VERSION 5.8 ;
BUSBITCHARS "[]" ;
DIVIDERCHAR "/" ;
UNITS
    DATABASE MICRONS 2000 ;
END UNITS

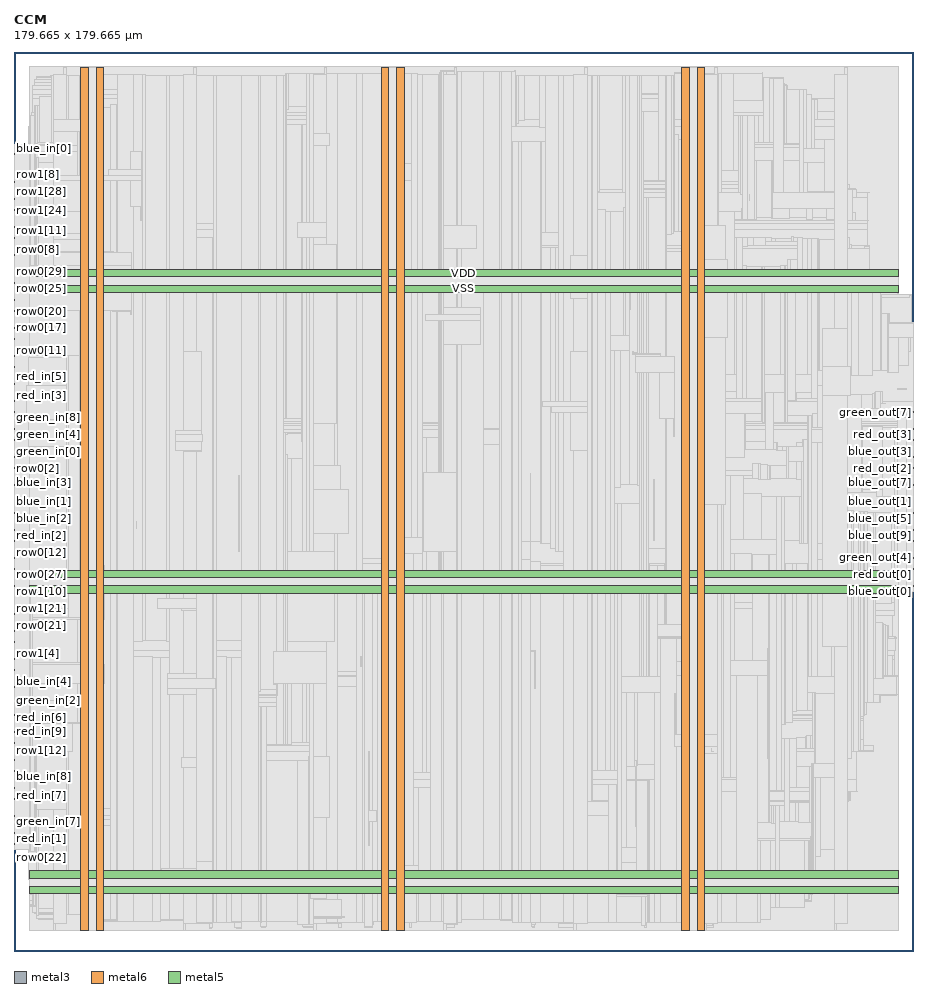
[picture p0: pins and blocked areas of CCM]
MACRO CCM
  FOREIGN CCM 0 0 ;
  CLASS BLOCK ;
  SIZE 179.665 BY 179.665 ;
  PIN blue_in[0]
    DIRECTION INPUT ;
    USE SIGNAL ;
    PORT
      LAYER metal3 ;
        RECT  0 160.195 0.07 160.265 ;
    END
  END blue_in[0]
  PIN blue_in[1]
    DIRECTION INPUT ;
    USE SIGNAL ;
    PORT
      LAYER metal3 ;
        RECT  0 89.635 0.07 89.705 ;
    END
  END blue_in[1]
  PIN blue_in[2]
    DIRECTION INPUT ;
    USE SIGNAL ;
    PORT
      LAYER metal3 ;
        RECT  0 86.275 0.07 86.345 ;
    END
  END blue_in[2]
  PIN blue_in[3]
    DIRECTION INPUT ;
    USE SIGNAL ;
    PORT
      LAYER metal3 ;
        RECT  0 91.875 0.07 91.945 ;
    END
  END blue_in[3]
  PIN blue_in[4]
    DIRECTION INPUT ;
    USE SIGNAL ;
    PORT
      LAYER metal3 ;
        RECT  0 53.795 0.07 53.865 ;
    END
  END blue_in[4]
  PIN blue_in[5]
    DIRECTION INPUT ;
    USE SIGNAL ;
    PORT
      LAYER metal3 ;
        RECT  0 88.515 0.07 88.585 ;
    END
  END blue_in[5]
  PIN blue_in[6]
    DIRECTION INPUT ;
    USE SIGNAL ;
    PORT
      LAYER metal3 ;
        RECT  0 94.115 0.07 94.185 ;
    END
  END blue_in[6]
  PIN blue_in[7]
    DIRECTION INPUT ;
    USE SIGNAL ;
    PORT
      LAYER metal3 ;
        RECT  0 95.235 0.07 95.305 ;
    END
  END blue_in[7]
  PIN blue_in[8]
    DIRECTION INPUT ;
    USE SIGNAL ;
    PORT
      LAYER metal3 ;
        RECT  0 34.755 0.07 34.825 ;
    END
  END blue_in[8]
  PIN blue_in[9]
    DIRECTION INPUT ;
    USE SIGNAL ;
    PORT
      LAYER metal3 ;
        RECT  0 52.675 0.07 52.745 ;
    END
  END blue_in[9]
  PIN blue_out[0]
    DIRECTION OUTPUT ;
    USE SIGNAL ;
    PORT
      LAYER metal3 ;
        RECT  179.595 71.715 179.665 71.785 ;
    END
  END blue_out[0]
  PIN blue_out[1]
    DIRECTION OUTPUT ;
    USE SIGNAL ;
    PORT
      LAYER metal3 ;
        RECT  179.595 89.635 179.665 89.705 ;
    END
  END blue_out[1]
  PIN blue_out[2]
    DIRECTION OUTPUT ;
    USE SIGNAL ;
    PORT
      LAYER metal3 ;
        RECT  179.595 104.195 179.665 104.265 ;
    END
  END blue_out[2]
  PIN blue_out[3]
    DIRECTION OUTPUT ;
    USE SIGNAL ;
    PORT
      LAYER metal3 ;
        RECT  179.595 99.715 179.665 99.785 ;
    END
  END blue_out[3]
  PIN blue_out[4]
    DIRECTION OUTPUT ;
    USE SIGNAL ;
    PORT
      LAYER metal3 ;
        RECT  179.595 94.115 179.665 94.185 ;
    END
  END blue_out[4]
  PIN blue_out[5]
    DIRECTION OUTPUT ;
    USE SIGNAL ;
    PORT
      LAYER metal3 ;
        RECT  179.595 86.275 179.665 86.345 ;
    END
  END blue_out[5]
  PIN blue_out[6]
    DIRECTION OUTPUT ;
    USE SIGNAL ;
    PORT
      LAYER metal3 ;
        RECT  179.595 85.155 179.665 85.225 ;
    END
  END blue_out[6]
  PIN blue_out[7]
    DIRECTION OUTPUT ;
    USE SIGNAL ;
    PORT
      LAYER metal3 ;
        RECT  179.595 91.875 179.665 91.945 ;
    END
  END blue_out[7]
  PIN blue_out[8]
    DIRECTION OUTPUT ;
    USE SIGNAL ;
    PORT
      LAYER metal3 ;
        RECT  179.595 100.835 179.665 100.905 ;
    END
  END blue_out[8]
  PIN blue_out[9]
    DIRECTION OUTPUT ;
    USE SIGNAL ;
    PORT
      LAYER metal3 ;
        RECT  179.595 82.915 179.665 82.985 ;
    END
  END blue_out[9]
  PIN clk
    DIRECTION INPUT ;
    USE SIGNAL ;
    PORT
      LAYER metal3 ;
        RECT  0 97.475 0.07 97.545 ;
    END
  END clk
  PIN coef_in
    DIRECTION INPUT ;
    USE SIGNAL ;
    PORT
      LAYER metal3 ;
        RECT  0 98.595 0.07 98.665 ;
    END
  END coef_in
  PIN green_in[0]
    DIRECTION INPUT ;
    USE SIGNAL ;
    PORT
      LAYER metal3 ;
        RECT  0 99.715 0.07 99.785 ;
    END
  END green_in[0]
  PIN green_in[1]
    DIRECTION INPUT ;
    USE SIGNAL ;
    PORT
      LAYER metal3 ;
        RECT  0 76.195 0.07 76.265 ;
    END
  END green_in[1]
  PIN green_in[2]
    DIRECTION INPUT ;
    USE SIGNAL ;
    PORT
      LAYER metal3 ;
        RECT  0 51.555 0.07 51.625 ;
    END
  END green_in[2]
  PIN green_in[3]
    DIRECTION INPUT ;
    USE SIGNAL ;
    PORT
      LAYER metal3 ;
        RECT  0 101.955 0.07 102.025 ;
    END
  END green_in[3]
  PIN green_in[4]
    DIRECTION INPUT ;
    USE SIGNAL ;
    PORT
      LAYER metal3 ;
        RECT  0 103.075 0.07 103.145 ;
    END
  END green_in[4]
  PIN green_in[5]
    DIRECTION INPUT ;
    USE SIGNAL ;
    PORT
      LAYER metal3 ;
        RECT  0 85.155 0.07 85.225 ;
    END
  END green_in[5]
  PIN green_in[6]
    DIRECTION INPUT ;
    USE SIGNAL ;
    PORT
      LAYER metal3 ;
        RECT  0 33.635 0.07 33.705 ;
    END
  END green_in[6]
  PIN green_in[7]
    DIRECTION INPUT ;
    USE SIGNAL ;
    PORT
      LAYER metal3 ;
        RECT  0 25.795 0.07 25.865 ;
    END
  END green_in[7]
  PIN green_in[8]
    DIRECTION INPUT ;
    USE SIGNAL ;
    PORT
      LAYER metal3 ;
        RECT  0 106.435 0.07 106.505 ;
    END
  END green_in[8]
  PIN green_in[9]
    DIRECTION INPUT ;
    USE SIGNAL ;
    PORT
      LAYER metal3 ;
        RECT  0 84.035 0.07 84.105 ;
    END
  END green_in[9]
  PIN green_out[0]
    DIRECTION OUTPUT ;
    USE SIGNAL ;
    PORT
      LAYER metal3 ;
        RECT  179.595 81.795 179.665 81.865 ;
    END
  END green_out[0]
  PIN green_out[1]
    DIRECTION OUTPUT ;
    USE SIGNAL ;
    PORT
      LAYER metal3 ;
        RECT  179.595 92.995 179.665 93.065 ;
    END
  END green_out[1]
  PIN green_out[2]
    DIRECTION OUTPUT ;
    USE SIGNAL ;
    PORT
      LAYER metal3 ;
        RECT  179.595 80.675 179.665 80.745 ;
    END
  END green_out[2]
  PIN green_out[3]
    DIRECTION OUTPUT ;
    USE SIGNAL ;
    PORT
      LAYER metal3 ;
        RECT  179.595 101.955 179.665 102.025 ;
    END
  END green_out[3]
  PIN green_out[4]
    DIRECTION OUTPUT ;
    USE SIGNAL ;
    PORT
      LAYER metal3 ;
        RECT  179.595 78.435 179.665 78.505 ;
    END
  END green_out[4]
  PIN green_out[5]
    DIRECTION OUTPUT ;
    USE SIGNAL ;
    PORT
      LAYER metal3 ;
        RECT  179.595 105.315 179.665 105.385 ;
    END
  END green_out[5]
  PIN green_out[6]
    DIRECTION OUTPUT ;
    USE SIGNAL ;
    PORT
      LAYER metal3 ;
        RECT  179.595 88.515 179.665 88.585 ;
    END
  END green_out[6]
  PIN green_out[7]
    DIRECTION OUTPUT ;
    USE SIGNAL ;
    PORT
      LAYER metal3 ;
        RECT  179.595 107.555 179.665 107.625 ;
    END
  END green_out[7]
  PIN green_out[8]
    DIRECTION OUTPUT ;
    USE SIGNAL ;
    PORT
      LAYER metal3 ;
        RECT  179.595 77.315 179.665 77.385 ;
    END
  END green_out[8]
  PIN green_out[9]
    DIRECTION OUTPUT ;
    USE SIGNAL ;
    PORT
      LAYER metal3 ;
        RECT  179.595 95.235 179.665 95.305 ;
    END
  END green_out[9]
  PIN h_sync
    DIRECTION INPUT ;
    USE SIGNAL ;
    PORT
      LAYER metal3 ;
        RECT  0 107.555 0.07 107.625 ;
    END
  END h_sync
  PIN h_sync_out
    DIRECTION OUTPUT ;
    USE SIGNAL ;
    PORT
      LAYER metal3 ;
        RECT  179.595 84.035 179.665 84.105 ;
    END
  END h_sync_out
  PIN red_in[0]
    DIRECTION INPUT ;
    USE SIGNAL ;
    PORT
      LAYER metal3 ;
        RECT  0 108.675 0.07 108.745 ;
    END
  END red_in[0]
  PIN red_in[1]
    DIRECTION INPUT ;
    USE SIGNAL ;
    PORT
      LAYER metal3 ;
        RECT  0 22.435 0.07 22.505 ;
    END
  END red_in[1]
  PIN red_in[2]
    DIRECTION INPUT ;
    USE SIGNAL ;
    PORT
      LAYER metal3 ;
        RECT  0 82.915 0.07 82.985 ;
    END
  END red_in[2]
  PIN red_in[3]
    DIRECTION INPUT ;
    USE SIGNAL ;
    PORT
      LAYER metal3 ;
        RECT  0 110.915 0.07 110.985 ;
    END
  END red_in[3]
  PIN red_in[4]
    DIRECTION INPUT ;
    USE SIGNAL ;
    PORT
      LAYER metal3 ;
        RECT  0 112.035 0.07 112.105 ;
    END
  END red_in[4]
  PIN red_in[5]
    DIRECTION INPUT ;
    USE SIGNAL ;
    PORT
      LAYER metal3 ;
        RECT  0 113.155 0.07 113.225 ;
    END
  END red_in[5]
  PIN red_in[6]
    DIRECTION INPUT ;
    USE SIGNAL ;
    PORT
      LAYER metal3 ;
        RECT  0 48.195 0.07 48.265 ;
    END
  END red_in[6]
  PIN red_in[7]
    DIRECTION INPUT ;
    USE SIGNAL ;
    PORT
      LAYER metal3 ;
        RECT  0 32.515 0.07 32.585 ;
    END
  END red_in[7]
  PIN red_in[8]
    DIRECTION INPUT ;
    USE SIGNAL ;
    PORT
      LAYER metal3 ;
        RECT  0 44.835 0.07 44.905 ;
    END
  END red_in[8]
  PIN red_in[9]
    DIRECTION INPUT ;
    USE SIGNAL ;
    PORT
      LAYER metal3 ;
        RECT  0 43.715 0.07 43.785 ;
    END
  END red_in[9]
  PIN red_out[0]
    DIRECTION OUTPUT ;
    USE SIGNAL ;
    PORT
      LAYER metal3 ;
        RECT  179.595 75.075 179.665 75.145 ;
    END
  END red_out[0]
  PIN red_out[1]
    DIRECTION OUTPUT ;
    USE SIGNAL ;
    PORT
      LAYER metal3 ;
        RECT  179.595 87.395 179.665 87.465 ;
    END
  END red_out[1]
  PIN red_out[2]
    DIRECTION OUTPUT ;
    USE SIGNAL ;
    PORT
      LAYER metal3 ;
        RECT  179.595 96.355 179.665 96.425 ;
    END
  END red_out[2]
  PIN red_out[3]
    DIRECTION OUTPUT ;
    USE SIGNAL ;
    PORT
      LAYER metal3 ;
        RECT  179.595 103.075 179.665 103.145 ;
    END
  END red_out[3]
  PIN red_out[4]
    DIRECTION OUTPUT ;
    USE SIGNAL ;
    PORT
      LAYER metal3 ;
        RECT  179.595 90.755 179.665 90.825 ;
    END
  END red_out[4]
  PIN red_out[5]
    DIRECTION OUTPUT ;
    USE SIGNAL ;
    PORT
      LAYER metal3 ;
        RECT  179.595 73.955 179.665 74.025 ;
    END
  END red_out[5]
  PIN red_out[6]
    DIRECTION OUTPUT ;
    USE SIGNAL ;
    PORT
      LAYER metal3 ;
        RECT  179.595 97.475 179.665 97.545 ;
    END
  END red_out[6]
  PIN red_out[7]
    DIRECTION OUTPUT ;
    USE SIGNAL ;
    PORT
      LAYER metal3 ;
        RECT  179.595 72.835 179.665 72.905 ;
    END
  END red_out[7]
  PIN red_out[8]
    DIRECTION OUTPUT ;
    USE SIGNAL ;
    PORT
      LAYER metal3 ;
        RECT  179.595 79.555 179.665 79.625 ;
    END
  END red_out[8]
  PIN red_out[9]
    DIRECTION OUTPUT ;
    USE SIGNAL ;
    PORT
      LAYER metal3 ;
        RECT  179.595 76.195 179.665 76.265 ;
    END
  END red_out[9]
  PIN resetn
    DIRECTION INPUT ;
    USE SIGNAL ;
    PORT
      LAYER metal3 ;
        RECT  0 80.675 0.07 80.745 ;
    END
  END resetn
  PIN row0[0]
    DIRECTION INPUT ;
    USE SIGNAL ;
    PORT
      LAYER metal3 ;
        RECT  0 47.075 0.07 47.145 ;
    END
  END row0[0]
  PIN row0[10]
    DIRECTION INPUT ;
    USE SIGNAL ;
    PORT
      LAYER metal3 ;
        RECT  0 118.755 0.07 118.825 ;
    END
  END row0[10]
  PIN row0[11]
    DIRECTION INPUT ;
    USE SIGNAL ;
    PORT
      LAYER metal3 ;
        RECT  0 119.875 0.07 119.945 ;
    END
  END row0[11]
  PIN row0[12]
    DIRECTION INPUT ;
    USE SIGNAL ;
    PORT
      LAYER metal3 ;
        RECT  0 79.555 0.07 79.625 ;
    END
  END row0[12]
  PIN row0[13]
    DIRECTION INPUT ;
    USE SIGNAL ;
    PORT
      LAYER metal3 ;
        RECT  0 115.395 0.07 115.465 ;
    END
  END row0[13]
  PIN row0[14]
    DIRECTION INPUT ;
    USE SIGNAL ;
    PORT
      LAYER metal3 ;
        RECT  0 45.955 0.07 46.025 ;
    END
  END row0[14]
  PIN row0[15]
    DIRECTION INPUT ;
    USE SIGNAL ;
    PORT
      LAYER metal3 ;
        RECT  0 123.235 0.07 123.305 ;
    END
  END row0[15]
  PIN row0[16]
    DIRECTION INPUT ;
    USE SIGNAL ;
    PORT
      LAYER metal3 ;
        RECT  0 78.435 0.07 78.505 ;
    END
  END row0[16]
  PIN row0[17]
    DIRECTION INPUT ;
    USE SIGNAL ;
    PORT
      LAYER metal3 ;
        RECT  0 124.355 0.07 124.425 ;
    END
  END row0[17]
  PIN row0[18]
    DIRECTION INPUT ;
    USE SIGNAL ;
    PORT
      LAYER metal3 ;
        RECT  0 125.475 0.07 125.545 ;
    END
  END row0[18]
  PIN row0[19]
    DIRECTION INPUT ;
    USE SIGNAL ;
    PORT
      LAYER metal3 ;
        RECT  0 31.395 0.07 31.465 ;
    END
  END row0[19]
  PIN row0[1]
    DIRECTION INPUT ;
    USE SIGNAL ;
    PORT
      LAYER metal3 ;
        RECT  0 77.315 0.07 77.385 ;
    END
  END row0[1]
  PIN row0[20]
    DIRECTION INPUT ;
    USE SIGNAL ;
    PORT
      LAYER metal3 ;
        RECT  0 127.715 0.07 127.785 ;
    END
  END row0[20]
  PIN row0[21]
    DIRECTION INPUT ;
    USE SIGNAL ;
    PORT
      LAYER metal3 ;
        RECT  0 64.995 0.07 65.065 ;
    END
  END row0[21]
  PIN row0[22]
    DIRECTION INPUT ;
    USE SIGNAL ;
    PORT
      LAYER metal3 ;
        RECT  0 20.195 0.07 20.265 ;
    END
  END row0[22]
  PIN row0[23]
    DIRECTION INPUT ;
    USE SIGNAL ;
    PORT
      LAYER metal3 ;
        RECT  0 24.675 0.07 24.745 ;
    END
  END row0[23]
  PIN row0[24]
    DIRECTION INPUT ;
    USE SIGNAL ;
    PORT
      LAYER metal3 ;
        RECT  0 81.795 0.07 81.865 ;
    END
  END row0[24]
  PIN row0[25]
    DIRECTION INPUT ;
    USE SIGNAL ;
    PORT
      LAYER metal3 ;
        RECT  0 132.195 0.07 132.265 ;
    END
  END row0[25]
  PIN row0[26]
    DIRECTION INPUT ;
    USE SIGNAL ;
    PORT
      LAYER metal3 ;
        RECT  0 128.835 0.07 128.905 ;
    END
  END row0[26]
  PIN row0[27]
    DIRECTION INPUT ;
    USE SIGNAL ;
    PORT
      LAYER metal3 ;
        RECT  0 75.075 0.07 75.145 ;
    END
  END row0[27]
  PIN row0[28]
    DIRECTION INPUT ;
    USE SIGNAL ;
    PORT
      LAYER metal3 ;
        RECT  0 104.195 0.07 104.265 ;
    END
  END row0[28]
  PIN row0[29]
    DIRECTION INPUT ;
    USE SIGNAL ;
    PORT
      LAYER metal3 ;
        RECT  0 135.555 0.07 135.625 ;
    END
  END row0[29]
  PIN row0[2]
    DIRECTION INPUT ;
    USE SIGNAL ;
    PORT
      LAYER metal3 ;
        RECT  0 96.355 0.07 96.425 ;
    END
  END row0[2]
  PIN row0[3]
    DIRECTION INPUT ;
    USE SIGNAL ;
    PORT
      LAYER metal3 ;
        RECT  0 73.955 0.07 74.025 ;
    END
  END row0[3]
  PIN row0[4]
    DIRECTION INPUT ;
    USE SIGNAL ;
    PORT
      LAYER metal3 ;
        RECT  0 42.595 0.07 42.665 ;
    END
  END row0[4]
  PIN row0[5]
    DIRECTION INPUT ;
    USE SIGNAL ;
    PORT
      LAYER metal3 ;
        RECT  0 30.275 0.07 30.345 ;
    END
  END row0[5]
  PIN row0[6]
    DIRECTION INPUT ;
    USE SIGNAL ;
    PORT
      LAYER metal3 ;
        RECT  0 138.915 0.07 138.985 ;
    END
  END row0[6]
  PIN row0[7]
    DIRECTION INPUT ;
    USE SIGNAL ;
    PORT
      LAYER metal3 ;
        RECT  0 72.835 0.07 72.905 ;
    END
  END row0[7]
  PIN row0[8]
    DIRECTION INPUT ;
    USE SIGNAL ;
    PORT
      LAYER metal3 ;
        RECT  0 140.035 0.07 140.105 ;
    END
  END row0[8]
  PIN row0[9]
    DIRECTION INPUT ;
    USE SIGNAL ;
    PORT
      LAYER metal3 ;
        RECT  0 141.155 0.07 141.225 ;
    END
  END row0[9]
  PIN row1[0]
    DIRECTION INPUT ;
    USE SIGNAL ;
    PORT
      LAYER metal3 ;
        RECT  0 126.595 0.07 126.665 ;
    END
  END row1[0]
  PIN row1[10]
    DIRECTION INPUT ;
    USE SIGNAL ;
    PORT
      LAYER metal3 ;
        RECT  0 71.715 0.07 71.785 ;
    END
  END row1[10]
  PIN row1[11]
    DIRECTION INPUT ;
    USE SIGNAL ;
    PORT
      LAYER metal3 ;
        RECT  0 142.275 0.07 142.345 ;
    END
  END row1[11]
  PIN row1[12]
    DIRECTION INPUT ;
    USE SIGNAL ;
    PORT
      LAYER metal3 ;
        RECT  0 41.475 0.07 41.545 ;
    END
  END row1[12]
  PIN row1[13]
    DIRECTION INPUT ;
    USE SIGNAL ;
    PORT
      LAYER metal3 ;
        RECT  0 116.515 0.07 116.585 ;
    END
  END row1[13]
  PIN row1[14]
    DIRECTION INPUT ;
    USE SIGNAL ;
    PORT
      LAYER metal3 ;
        RECT  0 70.595 0.07 70.665 ;
    END
  END row1[14]
  PIN row1[15]
    DIRECTION INPUT ;
    USE SIGNAL ;
    PORT
      LAYER metal3 ;
        RECT  0 117.635 0.07 117.705 ;
    END
  END row1[15]
  PIN row1[16]
    DIRECTION INPUT ;
    USE SIGNAL ;
    PORT
      LAYER metal3 ;
        RECT  0 144.515 0.07 144.585 ;
    END
  END row1[16]
  PIN row1[17]
    DIRECTION INPUT ;
    USE SIGNAL ;
    PORT
      LAYER metal3 ;
        RECT  0 145.635 0.07 145.705 ;
    END
  END row1[17]
  PIN row1[18]
    DIRECTION INPUT ;
    USE SIGNAL ;
    PORT
      LAYER metal3 ;
        RECT  0 69.475 0.07 69.545 ;
    END
  END row1[18]
  PIN row1[19]
    DIRECTION INPUT ;
    USE SIGNAL ;
    PORT
      LAYER metal3 ;
        RECT  0 109.795 0.07 109.865 ;
    END
  END row1[19]
  PIN row1[1]
    DIRECTION INPUT ;
    USE SIGNAL ;
    PORT
      LAYER metal3 ;
        RECT  0 29.155 0.07 29.225 ;
    END
  END row1[1]
  PIN row1[20]
    DIRECTION INPUT ;
    USE SIGNAL ;
    PORT
      LAYER metal3 ;
        RECT  0 105.315 0.07 105.385 ;
    END
  END row1[20]
  PIN row1[21]
    DIRECTION INPUT ;
    USE SIGNAL ;
    PORT
      LAYER metal3 ;
        RECT  0 68.355 0.07 68.425 ;
    END
  END row1[21]
  PIN row1[22]
    DIRECTION INPUT ;
    USE SIGNAL ;
    PORT
      LAYER metal3 ;
        RECT  0 40.355 0.07 40.425 ;
    END
  END row1[22]
  PIN row1[23]
    DIRECTION INPUT ;
    USE SIGNAL ;
    PORT
      LAYER metal3 ;
        RECT  0 100.835 0.07 100.905 ;
    END
  END row1[23]
  PIN row1[24]
    DIRECTION INPUT ;
    USE SIGNAL ;
    PORT
      LAYER metal3 ;
        RECT  0 147.875 0.07 147.945 ;
    END
  END row1[24]
  PIN row1[25]
    DIRECTION INPUT ;
    USE SIGNAL ;
    PORT
      LAYER metal3 ;
        RECT  0 67.235 0.07 67.305 ;
    END
  END row1[25]
  PIN row1[26]
    DIRECTION INPUT ;
    USE SIGNAL ;
    PORT
      LAYER metal3 ;
        RECT  0 148.995 0.07 149.065 ;
    END
  END row1[26]
  PIN row1[27]
    DIRECTION INPUT ;
    USE SIGNAL ;
    PORT
      LAYER metal3 ;
        RECT  0 92.995 0.07 93.065 ;
    END
  END row1[27]
  PIN row1[28]
    DIRECTION INPUT ;
    USE SIGNAL ;
    PORT
      LAYER metal3 ;
        RECT  0 150.115 0.07 150.185 ;
    END
  END row1[28]
  PIN row1[29]
    DIRECTION INPUT ;
    USE SIGNAL ;
    PORT
      LAYER metal3 ;
        RECT  0 66.115 0.07 66.185 ;
    END
  END row1[29]
  PIN row1[2]
    DIRECTION INPUT ;
    USE SIGNAL ;
    PORT
      LAYER metal3 ;
        RECT  0 136.675 0.07 136.745 ;
    END
  END row1[2]
  PIN row1[3]
    DIRECTION INPUT ;
    USE SIGNAL ;
    PORT
      LAYER metal3 ;
        RECT  0 39.235 0.07 39.305 ;
    END
  END row1[3]
  PIN row1[4]
    DIRECTION INPUT ;
    USE SIGNAL ;
    PORT
      LAYER metal3 ;
        RECT  0 59.395 0.07 59.465 ;
    END
  END row1[4]
  PIN row1[5]
    DIRECTION INPUT ;
    USE SIGNAL ;
    PORT
      LAYER metal3 ;
        RECT  0 23.555 0.07 23.625 ;
    END
  END row1[5]
  PIN row1[6]
    DIRECTION INPUT ;
    USE SIGNAL ;
    PORT
      LAYER metal3 ;
        RECT  0 151.235 0.07 151.305 ;
    END
  END row1[6]
  PIN row1[7]
    DIRECTION INPUT ;
    USE SIGNAL ;
    PORT
      LAYER metal3 ;
        RECT  0 134.435 0.07 134.505 ;
    END
  END row1[7]
  PIN row1[8]
    DIRECTION INPUT ;
    USE SIGNAL ;
    PORT
      LAYER metal3 ;
        RECT  0 153.475 0.07 153.545 ;
    END
  END row1[8]
  PIN row1[9]
    DIRECTION INPUT ;
    USE SIGNAL ;
    PORT
      LAYER metal3 ;
        RECT  0 63.875 0.07 63.945 ;
    END
  END row1[9]
  PIN row2[0]
    DIRECTION INPUT ;
    USE SIGNAL ;
    PORT
      LAYER metal3 ;
        RECT  0 87.395 0.07 87.465 ;
    END
  END row2[0]
  PIN row2[10]
    DIRECTION INPUT ;
    USE SIGNAL ;
    PORT
      LAYER metal3 ;
        RECT  0 146.755 0.07 146.825 ;
    END
  END row2[10]
  PIN row2[11]
    DIRECTION INPUT ;
    USE SIGNAL ;
    PORT
      LAYER metal3 ;
        RECT  0 143.395 0.07 143.465 ;
    END
  END row2[11]
  PIN row2[12]
    DIRECTION INPUT ;
    USE SIGNAL ;
    PORT
      LAYER metal3 ;
        RECT  0 62.755 0.07 62.825 ;
    END
  END row2[12]
  PIN row2[13]
    DIRECTION INPUT ;
    USE SIGNAL ;
    PORT
      LAYER metal3 ;
        RECT  0 28.035 0.07 28.105 ;
    END
  END row2[13]
  PIN row2[14]
    DIRECTION INPUT ;
    USE SIGNAL ;
    PORT
      LAYER metal3 ;
        RECT  0 38.115 0.07 38.185 ;
    END
  END row2[14]
  PIN row2[15]
    DIRECTION INPUT ;
    USE SIGNAL ;
    PORT
      LAYER metal3 ;
        RECT  0 114.275 0.07 114.345 ;
    END
  END row2[15]
  PIN row2[16]
    DIRECTION INPUT ;
    USE SIGNAL ;
    PORT
      LAYER metal3 ;
        RECT  0 61.635 0.07 61.705 ;
    END
  END row2[16]
  PIN row2[17]
    DIRECTION INPUT ;
    USE SIGNAL ;
    PORT
      LAYER metal3 ;
        RECT  0 56.035 0.07 56.105 ;
    END
  END row2[17]
  PIN row2[18]
    DIRECTION INPUT ;
    USE SIGNAL ;
    PORT
      LAYER metal3 ;
        RECT  0 154.595 0.07 154.665 ;
    END
  END row2[18]
  PIN row2[19]
    DIRECTION INPUT ;
    USE SIGNAL ;
    PORT
      LAYER metal3 ;
        RECT  0 137.795 0.07 137.865 ;
    END
  END row2[19]
  PIN row2[1]
    DIRECTION INPUT ;
    USE SIGNAL ;
    PORT
      LAYER metal3 ;
        RECT  0 60.515 0.07 60.585 ;
    END
  END row2[1]
  PIN row2[20]
    DIRECTION INPUT ;
    USE SIGNAL ;
    PORT
      LAYER metal3 ;
        RECT  0 122.115 0.07 122.185 ;
    END
  END row2[20]
  PIN row2[21]
    DIRECTION INPUT ;
    USE SIGNAL ;
    PORT
      LAYER metal3 ;
        RECT  0 155.715 0.07 155.785 ;
    END
  END row2[21]
  PIN row2[22]
    DIRECTION INPUT ;
    USE SIGNAL ;
    PORT
      LAYER metal3 ;
        RECT  0 156.835 0.07 156.905 ;
    END
  END row2[22]
  PIN row2[23]
    DIRECTION INPUT ;
    USE SIGNAL ;
    PORT
      LAYER metal3 ;
        RECT  0 36.995 0.07 37.065 ;
    END
  END row2[23]
  PIN row2[24]
    DIRECTION INPUT ;
    USE SIGNAL ;
    PORT
      LAYER metal3 ;
        RECT  0 129.955 0.07 130.025 ;
    END
  END row2[24]
  PIN row2[25]
    DIRECTION INPUT ;
    USE SIGNAL ;
    PORT
      LAYER metal3 ;
        RECT  0 131.075 0.07 131.145 ;
    END
  END row2[25]
  PIN row2[26]
    DIRECTION INPUT ;
    USE SIGNAL ;
    PORT
      LAYER metal3 ;
        RECT  0 157.955 0.07 158.025 ;
    END
  END row2[26]
  PIN row2[27]
    DIRECTION INPUT ;
    USE SIGNAL ;
    PORT
      LAYER metal3 ;
        RECT  0 58.275 0.07 58.345 ;
    END
  END row2[27]
  PIN row2[28]
    DIRECTION INPUT ;
    USE SIGNAL ;
    PORT
      LAYER metal3 ;
        RECT  0 159.075 0.07 159.145 ;
    END
  END row2[28]
  PIN row2[29]
    DIRECTION INPUT ;
    USE SIGNAL ;
    PORT
      LAYER metal3 ;
        RECT  0 26.915 0.07 26.985 ;
    END
  END row2[29]
  PIN row2[2]
    DIRECTION INPUT ;
    USE SIGNAL ;
    PORT
      LAYER metal3 ;
        RECT  0 21.315 0.07 21.385 ;
    END
  END row2[2]
  PIN row2[3]
    DIRECTION INPUT ;
    USE SIGNAL ;
    PORT
      LAYER metal3 ;
        RECT  0 57.155 0.07 57.225 ;
    END
  END row2[3]
  PIN row2[4]
    DIRECTION INPUT ;
    USE SIGNAL ;
    PORT
      LAYER metal3 ;
        RECT  0 120.995 0.07 121.065 ;
    END
  END row2[4]
  PIN row2[5]
    DIRECTION INPUT ;
    USE SIGNAL ;
    PORT
      LAYER metal3 ;
        RECT  0 133.315 0.07 133.385 ;
    END
  END row2[5]
  PIN row2[6]
    DIRECTION INPUT ;
    USE SIGNAL ;
    PORT
      LAYER metal3 ;
        RECT  0 50.435 0.07 50.505 ;
    END
  END row2[6]
  PIN row2[7]
    DIRECTION INPUT ;
    USE SIGNAL ;
    PORT
      LAYER metal3 ;
        RECT  0 35.875 0.07 35.945 ;
    END
  END row2[7]
  PIN row2[8]
    DIRECTION INPUT ;
    USE SIGNAL ;
    PORT
      LAYER metal3 ;
        RECT  0 90.755 0.07 90.825 ;
    END
  END row2[8]
  PIN row2[9]
    DIRECTION INPUT ;
    USE SIGNAL ;
    PORT
      LAYER metal3 ;
        RECT  0 49.315 0.07 49.385 ;
    END
  END row2[9]
  PIN v_sync
    DIRECTION INPUT ;
    USE SIGNAL ;
    PORT
      LAYER metal3 ;
        RECT  0 152.355 0.07 152.425 ;
    END
  END v_sync
  PIN v_sync_out
    DIRECTION OUTPUT ;
    USE SIGNAL ;
    PORT
      LAYER metal3 ;
        RECT  179.595 98.595 179.665 98.665 ;
    END
  END v_sync_out
  PIN valid_in
    DIRECTION INPUT ;
    USE SIGNAL ;
    PORT
      LAYER metal3 ;
        RECT  0 54.915 0.07 54.985 ;
    END
  END valid_in
  PIN valid_out
    DIRECTION OUTPUT ;
    USE SIGNAL ;
    PORT
      LAYER metal3 ;
        RECT  179.595 106.435 179.665 106.505 ;
    END
  END valid_out
  PIN VSS
    DIRECTION INOUT ;
    USE GROUND ;
    PORT
      LAYER metal6 ;
        RECT  133.29 4.16 134.79 176.44 ;
        RECT  73.29 4.16 74.79 176.44 ;
        RECT  13.29 4.16 14.79 176.44 ;
      LAYER metal5 ;
        RECT  3.04 131.45 176.51 132.95 ;
        RECT  3.04 71.45 176.51 72.95 ;
        RECT  3.04 11.45 176.51 12.95 ;
    END
  END VSS
  PIN VDD
    DIRECTION INOUT ;
    USE POWER ;
    PORT
      LAYER metal6 ;
        RECT  136.39 4.16 137.89 176.44 ;
        RECT  76.39 4.16 77.89 176.44 ;
        RECT  16.39 4.16 17.89 176.44 ;
      LAYER metal5 ;
        RECT  3.04 134.55 176.51 136.05 ;
        RECT  3.04 74.55 176.51 76.05 ;
        RECT  3.04 14.55 176.51 16.05 ;
    END
  END VDD
  OBS
    LAYER metal1 ;
     RECT  3.04 4.115 176.51 176.485 ;
    LAYER metal2 ;
     RECT  39.39 4.48 39.46 4.515 ;
     RECT  44.33 4.48 44.4 4.515 ;
     RECT  39.01 4.515 39.46 4.76 ;
     RECT  44.33 4.515 45.35 4.76 ;
     RECT  50.03 4.62 50.1 4.76 ;
     RECT  59.81 4.13 60.27 4.76 ;
     RECT  85.81 4.13 86.27 4.76 ;
     RECT  111.81 4.13 112.27 4.76 ;
     RECT  137.81 4.13 138.27 4.76 ;
     RECT  49.46 4.76 50.29 4.795 ;
     RECT  57.82 4.76 60.27 4.795 ;
     RECT  103.42 4.76 103.87 4.795 ;
     RECT  125.84 4.76 126.29 5.04 ;
     RECT  57.63 4.795 60.27 5.32 ;
     RECT  85.81 4.76 87.91 5.32 ;
     RECT  69.98 4.76 71.57 5.355 ;
     RECT  103.23 4.795 103.87 5.355 ;
     RECT  7.81 4.13 8.27 5.53 ;
     RECT  33.81 4.13 34.27 5.53 ;
     RECT  39.01 4.76 39.65 5.53 ;
     RECT  56.68 5.32 60.27 5.53 ;
     RECT  64.85 4.76 65.3 5.53 ;
     RECT  85.81 5.32 88.1 5.53 ;
     RECT  108.74 4.76 112.27 5.53 ;
     RECT  137.81 4.76 139.59 5.53 ;
     RECT  163.81 4.13 164.27 5.53 ;
     RECT  69.98 5.355 71.76 5.6 ;
     RECT  33.81 5.53 39.65 5.665 ;
     RECT  56.68 5.53 65.3 5.665 ;
     RECT  33.81 5.665 40.03 5.74 ;
     RECT  43.95 4.76 45.35 5.74 ;
     RECT  56.68 5.665 65.49 5.74 ;
     RECT  69.41 5.6 71.76 5.74 ;
     RECT  78.91 4.76 79.36 5.74 ;
     RECT  85.81 5.53 88.37 5.74 ;
     RECT  103.23 5.355 104.06 5.74 ;
     RECT  15.83 5.74 17.23 5.88 ;
     RECT  33.81 5.74 45.35 5.88 ;
     RECT  49.27 4.795 50.48 5.88 ;
     RECT  56.68 5.74 71.76 5.88 ;
     RECT  75.68 5.74 80.31 5.88 ;
     RECT  119 5.74 120.97 5.88 ;
     RECT  137.81 5.53 140.37 5.88 ;
     RECT  146.93 5.74 148.9 5.88 ;
     RECT  15.83 5.88 29.2 6.02 ;
     RECT  33.81 5.88 50.48 6.02 ;
     RECT  56.68 5.88 80.31 6.02 ;
     RECT  85.81 5.74 89.24 6.02 ;
     RECT  99.62 5.74 104.06 6.02 ;
     RECT  108.74 5.53 114.37 6.02 ;
     RECT  119 5.88 121.16 6.02 ;
     RECT  125.27 5.04 126.29 6.02 ;
     RECT  130.97 5.88 131.04 6.02 ;
     RECT  137.81 5.88 148.9 6.02 ;
     RECT  15.83 6.02 50.48 6.055 ;
     RECT  97.91 6.02 121.16 6.055 ;
     RECT  125.27 6.02 148.9 6.055 ;
     RECT  7.81 5.53 10.37 6.3 ;
     RECT  15.64 6.055 50.48 6.3 ;
     RECT  54.78 6.02 89.24 6.3 ;
     RECT  97.15 6.055 148.9 6.3 ;
     RECT  4.81 6.3 10.37 6.44 ;
     RECT  14.88 6.3 150.99 7.14 ;
     RECT  4.43 6.44 10.37 7.28 ;
     RECT  14.5 7.14 150.99 7.28 ;
     RECT  4.43 7.28 150.99 7.56 ;
     RECT  4.05 7.56 150.99 7.595 ;
     RECT  3.67 7.595 150.99 8.96 ;
     RECT  3.1 8.96 150.99 9.38 ;
     RECT  157.76 8.68 157.83 9.52 ;
     RECT  155.67 9.52 157.83 9.94 ;
     RECT  155.67 9.94 158.59 9.975 ;
     RECT  3.1 9.38 151.37 10.08 ;
     RECT  155.67 9.975 159.16 10.08 ;
     RECT  3.1 10.08 159.16 11.2 ;
     RECT  3.1 11.2 159.35 11.48 ;
     RECT  3.1 11.48 159.54 12.18 ;
     RECT  163.81 5.53 166.37 12.18 ;
     RECT  3.1 12.18 166.37 14.28 ;
     RECT  2.91 14.28 166.37 22.4 ;
     RECT  2.72 22.4 166.37 26.18 ;
     RECT  2.72 26.18 166.38 27.055 ;
     RECT  2.53 27.055 166.38 29.82 ;
     RECT  2.53 29.82 166.57 29.96 ;
     RECT  2.53 29.96 166.95 31.78 ;
     RECT  2.53 31.78 168.28 34.16 ;
     RECT  2.34 34.16 168.28 39.76 ;
     RECT  2.34 39.76 168.47 39.9 ;
     RECT  2.34 39.9 171.51 41.02 ;
     RECT  2.34 41.02 169.61 41.86 ;
     RECT  120.71 41.86 169.61 45.92 ;
     RECT  2.72 41.86 116.22 46.34 ;
     RECT  120.14 45.92 169.61 46.34 ;
     RECT  2.72 46.34 169.61 47.04 ;
     RECT  2.72 47.04 169.8 47.18 ;
     RECT  2.72 47.18 170.18 49.56 ;
     RECT  2.72 49.56 173.03 50.54 ;
     RECT  2.53 50.54 173.03 51.1 ;
     RECT  2.53 51.1 176.26 51.24 ;
     RECT  2.34 51.24 176.26 54.74 ;
     RECT  2.15 54.74 176.26 54.88 ;
     RECT  2.15 54.88 176.45 55.02 ;
     RECT  2.15 55.02 175.69 58.24 ;
     RECT  1.96 58.24 175.69 59.92 ;
     RECT  1.96 59.92 176.07 62.58 ;
     RECT  1.96 62.58 175.88 62.86 ;
     RECT  1.96 62.86 175.31 66.92 ;
     RECT  1.96 66.92 175.69 68.04 ;
     RECT  1.77 68.04 175.69 69.58 ;
     RECT  1.77 69.58 175.5 73.78 ;
     RECT  1.77 73.78 176.45 77.28 ;
     RECT  1.77 77.28 179.49 83.58 ;
     RECT  1.96 83.58 179.49 84.42 ;
     RECT  2.34 84.42 179.49 95.865 ;
     RECT  2.53 95.865 179.49 104.02 ;
     RECT  2.15 104.02 179.49 104.86 ;
     RECT  1.96 104.86 179.49 105.28 ;
     RECT  1.77 105.28 179.49 105.7 ;
     RECT  0.44 105.7 179.49 109.62 ;
     RECT  0.06 109.62 179.49 125.44 ;
     RECT  0.06 125.44 179.11 131.04 ;
     RECT  0.06 131.04 176.45 131.88 ;
     RECT  0.06 131.88 173.41 132.44 ;
     RECT  0.06 132.44 173.03 132.58 ;
     RECT  0.06 132.58 170.75 140.14 ;
     RECT  0.25 140.14 170.75 140.84 ;
     RECT  0.25 140.84 170.37 144.06 ;
     RECT  0.06 144.06 170.37 145.18 ;
     RECT  0.25 145.18 170.37 145.74 ;
     RECT  0.25 145.74 170.56 145.88 ;
     RECT  0.25 145.88 170.37 151.34 ;
     RECT  0.25 151.34 170.75 151.48 ;
     RECT  0.25 151.48 168.09 152.04 ;
     RECT  0.25 152.04 167.9 152.285 ;
     RECT  0.25 152.285 166.76 152.985 ;
     RECT  0.25 152.985 166.38 153.02 ;
     RECT  0.25 153.02 166.37 153.58 ;
     RECT  2.91 153.58 166.37 160.44 ;
     RECT  2.72 160.44 166.37 160.965 ;
     RECT  2.91 160.965 166.37 164.5 ;
     RECT  3.1 164.5 166.37 165.9 ;
     RECT  3.29 165.9 166.37 166.88 ;
     RECT  3.48 166.88 166.37 167.3 ;
     RECT  3.67 167.3 166.37 170.1 ;
     RECT  3.67 170.1 159.16 171.08 ;
     RECT  3.67 171.08 158.21 171.885 ;
     RECT  3.67 171.885 120.4 171.92 ;
     RECT  124.7 171.885 158.21 171.92 ;
     RECT  124.7 171.92 154.41 172.06 ;
     RECT  3.67 171.92 118.88 172.725 ;
     RECT  125.65 172.06 154.41 172.865 ;
     RECT  125.65 172.865 154.22 172.9 ;
     RECT  125.65 172.9 153.84 173.18 ;
     RECT  4.05 172.725 118.88 173.32 ;
     RECT  4.05 173.32 114.37 173.885 ;
     RECT  125.65 173.18 153.65 173.885 ;
     RECT  125.65 173.885 143.58 174.16 ;
     RECT  4.43 173.885 114.37 174.3 ;
     RECT  4.43 174.3 76.32 174.44 ;
     RECT  80.43 174.3 114.37 174.44 ;
     RECT  147.5 173.885 153.65 174.44 ;
     RECT  4.43 174.44 40.79 174.58 ;
     RECT  45.09 174.44 45.16 174.58 ;
     RECT  49.65 174.44 49.72 174.58 ;
     RECT  54.21 174.44 64.54 174.58 ;
     RECT  76.25 174.44 76.32 174.58 ;
     RECT  80.43 174.44 107.67 174.58 ;
     RECT  111.78 174.44 114.37 174.58 ;
     RECT  7.28 174.58 27.68 174.685 ;
     RECT  31.79 174.58 38.7 174.685 ;
     RECT  55.35 174.58 64.54 174.685 ;
     RECT  80.43 174.58 100.26 174.685 ;
     RECT  125.65 174.16 127.05 174.685 ;
     RECT  131.16 174.16 143.58 174.685 ;
     RECT  7.28 174.685 15.71 174.72 ;
     RECT  20.39 174.685 27.3 174.72 ;
     RECT  32.74 174.685 36.37 174.72 ;
     RECT  80.43 174.685 95.51 174.72 ;
     RECT  99.62 174.685 100.26 174.72 ;
     RECT  104.94 174.58 107.67 174.72 ;
     RECT  125.65 174.685 126.67 174.72 ;
     RECT  131.16 174.685 143.2 174.72 ;
     RECT  7.81 174.72 15.71 174.825 ;
     RECT  80.43 174.72 93.23 174.825 ;
     RECT  131.16 174.72 142.82 174.825 ;
     RECT  7.81 174.825 15.52 174.86 ;
     RECT  58.77 174.685 64.54 174.86 ;
     RECT  80.43 174.825 91.33 174.86 ;
     RECT  125.65 174.72 126.29 174.86 ;
     RECT  131.16 174.825 140.37 174.86 ;
     RECT  15.07 174.86 15.14 175 ;
     RECT  26.09 174.72 26.16 175 ;
     RECT  59.81 174.86 64.35 175 ;
     RECT  68.46 174.44 71.38 175 ;
     RECT  80.43 174.86 88.37 175 ;
     RECT  148.45 174.44 149.47 175 ;
     RECT  7.81 174.86 10.37 175.07 ;
     RECT  33.81 174.72 36.37 175.07 ;
     RECT  59.81 175 63.97 175.07 ;
     RECT  111.81 174.58 114.37 175.07 ;
     RECT  131.92 174.86 140.37 175.07 ;
     RECT  163.81 170.1 166.37 175.07 ;
     RECT  61.91 175.07 63.97 175.14 ;
     RECT  71.12 175 71.19 175.14 ;
     RECT  80.43 175 80.5 175.14 ;
     RECT  84.99 175 88.37 175.28 ;
     RECT  131.92 175.07 135.98 175.28 ;
     RECT  149.4 175 149.47 175.28 ;
     RECT  85.18 175.28 88.37 175.7 ;
     RECT  100 174.72 100.07 175.7 ;
     RECT  135.15 175.28 135.98 175.7 ;
     RECT  135.15 175.7 135.79 175.945 ;
     RECT  135.72 175.945 135.79 175.98 ;
     RECT  9.91 175.07 10.37 176.47 ;
     RECT  35.91 175.07 36.37 176.47 ;
     RECT  61.91 175.14 62.37 176.47 ;
     RECT  87.91 175.7 88.37 176.47 ;
     RECT  113.91 175.07 114.37 176.47 ;
     RECT  139.91 175.07 140.37 176.47 ;
     RECT  165.91 175.07 166.37 176.47 ;
    LAYER metal3 ;
     RECT  0 24.815 0.035 29.085 ;
     RECT  0 32.655 0.035 35.805 ;
     RECT  0 40.635 0.035 42.525 ;
     RECT  0 46.095 0.035 50.365 ;
     RECT  0 54.215 0.035 54.845 ;
     RECT  0 58.555 0.035 79.485 ;
     RECT  0 82.635 0.035 82.845 ;
     RECT  0 87.535 0.035 96.285 ;
     RECT  0 102.095 0.035 114.625 ;
     RECT  0 117.775 0.035 136.605 ;
     RECT  0.025 140.035 0.035 140.105 ;
     RECT  0 143.535 0.035 160.965 ;
     RECT  2.875 14.315 3.065 14.385 ;
     RECT  0.035 20.195 3.065 160.965 ;
     RECT  2.875 164.395 3.065 164.465 ;
     RECT  3.065 19.915 3.255 165.865 ;
     RECT  3.065 8.995 3.635 9.065 ;
     RECT  3.065 14.315 3.635 14.665 ;
     RECT  3.635 8.995 3.825 14.665 ;
     RECT  3.255 19.915 4.015 166.845 ;
     RECT  3.825 8.995 4.205 15.785 ;
     RECT  4.015 19.915 4.205 168.805 ;
     RECT  4.205 19.775 4.345 168.805 ;
     RECT  4.205 8.995 4.395 16.065 ;
     RECT  4.345 19.775 4.395 158.305 ;
     RECT  4.345 161.175 4.725 168.805 ;
     RECT  4.395 7.175 4.915 158.305 ;
     RECT  4.725 161.315 5.155 168.805 ;
     RECT  4.775 174.335 7.245 174.405 ;
     RECT  5.155 161.315 7.435 170.625 ;
     RECT  7.245 174.335 7.435 174.685 ;
     RECT  4.915 8.575 7.81 157.325 ;
     RECT  7.435 161.315 7.81 174.685 ;
     RECT  7.81 4.13 8.27 175.07 ;
     RECT  8.27 5.53 9.91 175.07 ;
     RECT  9.91 5.53 10.37 176.47 ;
     RECT  10.37 7.315 10.805 174.825 ;
     RECT  10.805 75.355 13.085 174.825 ;
     RECT  13.085 89.215 14.215 174.825 ;
     RECT  10.805 7.315 14.415 72.485 ;
     RECT  14.215 89.215 14.795 174.965 ;
     RECT  14.415 7.315 14.845 25.025 ;
     RECT  14.845 6.755 15.225 25.025 ;
     RECT  15.225 6.615 15.795 25.025 ;
     RECT  13.085 75.355 16.935 86.205 ;
     RECT  14.795 89.215 16.935 168.385 ;
     RECT  15.795 5.775 17.265 25.025 ;
     RECT  14.415 28.455 17.505 72.485 ;
     RECT  16.935 75.355 17.505 168.385 ;
     RECT  17.265 6.335 19.215 25.025 ;
     RECT  17.505 28.455 19.215 168.385 ;
     RECT  19.215 6.335 20.545 168.945 ;
     RECT  20.545 5.915 20.735 168.945 ;
     RECT  14.795 171.955 20.735 174.965 ;
     RECT  20.735 5.915 23.915 174.965 ;
     RECT  23.915 61.775 25.625 174.965 ;
     RECT  25.625 62.055 26.195 174.965 ;
     RECT  23.915 5.915 27.715 58.765 ;
     RECT  27.715 5.915 29.235 58.625 ;
     RECT  26.195 62.055 30.425 174.825 ;
     RECT  29.235 6.195 30.995 58.625 ;
     RECT  30.425 61.775 30.995 174.825 ;
     RECT  30.995 6.195 33.81 174.825 ;
     RECT  33.81 4.13 34.27 175.07 ;
     RECT  34.27 5.53 35.91 175.07 ;
     RECT  35.91 5.53 36.37 176.47 ;
     RECT  36.37 5.775 36.455 142.345 ;
     RECT  36.455 5.775 39.545 15.085 ;
     RECT  36.455 17.955 39.545 142.345 ;
     RECT  39.545 5.775 39.925 142.345 ;
     RECT  36.37 145.215 39.925 174.825 ;
     RECT  39.925 5.775 40.445 174.825 ;
     RECT  40.445 5.775 42.345 58.765 ;
     RECT  42.345 5.775 43.485 58.625 ;
     RECT  43.485 5.915 45.435 58.625 ;
     RECT  40.445 62.055 45.435 174.825 ;
     RECT  45.435 5.915 48.805 174.825 ;
     RECT  48.805 51.835 49.185 174.825 ;
     RECT  48.805 5.915 49.235 48.825 ;
     RECT  49.235 5.775 49.41 48.825 ;
     RECT  49.41 5.915 50.325 48.825 ;
     RECT  50.325 41.195 52.385 48.825 ;
     RECT  49.185 52.255 52.385 174.825 ;
     RECT  52.385 41.195 53.745 174.825 ;
     RECT  53.745 106.295 54.115 174.825 ;
     RECT  53.745 41.195 54.125 103.425 ;
     RECT  54.115 106.295 54.315 175.245 ;
     RECT  54.125 41.195 54.505 99.085 ;
     RECT  54.125 103.075 54.505 103.425 ;
     RECT  54.505 41.195 54.695 98.525 ;
     RECT  54.315 168.035 54.885 175.245 ;
     RECT  54.695 41.195 55.455 98.385 ;
     RECT  50.325 5.915 56.645 38.045 ;
     RECT  54.505 103.355 57.405 103.425 ;
     RECT  54.315 106.295 57.405 165.025 ;
     RECT  55.455 41.615 57.595 98.385 ;
     RECT  57.405 101.675 57.595 165.025 ;
     RECT  57.595 41.615 58.355 165.025 ;
     RECT  54.885 168.595 58.355 175.245 ;
     RECT  56.645 5.355 58.735 38.045 ;
     RECT  58.735 5.355 58.925 38.745 ;
     RECT  58.355 41.615 58.925 175.245 ;
     RECT  58.925 5.355 59.81 175.245 ;
     RECT  59.81 4.13 60.27 175.245 ;
     RECT  60.27 5.53 61.91 175.245 ;
     RECT  61.91 5.53 62.37 176.47 ;
     RECT  62.37 5.635 64.575 175.105 ;
     RECT  64.575 5.635 68.425 52.885 ;
     RECT  64.575 55.755 68.425 175.105 ;
     RECT  68.425 5.635 69.515 175.105 ;
     RECT  69.515 5.635 69.945 75.285 ;
     RECT  69.945 4.795 71.605 75.285 ;
     RECT  71.605 5.915 72.605 75.285 ;
     RECT  72.605 5.915 73.555 75.565 ;
     RECT  69.515 78.435 73.555 175.105 ;
     RECT  73.555 5.915 74.645 175.105 ;
     RECT  74.645 5.915 75.645 153.825 ;
     RECT  74.645 156.975 76.165 175.105 ;
     RECT  75.645 5.775 76.355 153.825 ;
     RECT  76.355 5.775 77.305 79.345 ;
     RECT  76.355 82.635 79.445 153.825 ;
     RECT  76.165 157.115 79.445 175.105 ;
     RECT  77.305 17.115 79.775 79.345 ;
     RECT  77.305 5.775 80.345 12.985 ;
     RECT  80.345 5.915 80.395 12.985 ;
     RECT  79.445 82.635 80.535 175.105 ;
     RECT  80.395 5.915 80.775 13.265 ;
     RECT  79.775 17.115 80.775 32.725 ;
     RECT  80.535 82.635 81.485 174.965 ;
     RECT  79.775 35.595 81.535 79.345 ;
     RECT  81.485 82.635 81.535 102.585 ;
     RECT  81.535 35.595 82.435 102.585 ;
     RECT  80.775 5.915 83.055 32.725 ;
     RECT  82.435 35.595 83.055 72.065 ;
     RECT  82.435 75.215 84.765 102.585 ;
     RECT  81.485 105.595 84.765 174.965 ;
     RECT  84.765 75.215 84.955 174.965 ;
     RECT  84.955 75.215 85.145 175.245 ;
     RECT  83.055 5.915 85.335 72.065 ;
     RECT  85.145 75.215 85.335 175.665 ;
     RECT  85.335 5.915 85.81 175.665 ;
     RECT  85.81 4.13 86.27 175.665 ;
     RECT  86.27 5.355 87.91 175.665 ;
     RECT  87.91 5.355 88.37 176.47 ;
     RECT  88.37 5.355 88.61 175.665 ;
     RECT  88.61 5.775 89.275 175.665 ;
     RECT  89.275 6.335 93.645 175.665 ;
     RECT  93.645 6.335 96.925 101.185 ;
     RECT  93.645 104.335 96.925 175.665 ;
     RECT  96.925 6.335 97.34 175.665 ;
     RECT  97.34 6.195 99.345 175.665 ;
     RECT  99.345 6.195 99.585 161.665 ;
     RECT  99.345 164.675 100.105 175.665 ;
     RECT  100.105 164.675 100.295 174.825 ;
     RECT  99.585 5.775 100.675 161.665 ;
     RECT  100.295 165.235 100.675 174.825 ;
     RECT  100.675 5.775 101.245 161.525 ;
     RECT  100.675 165.795 101.815 174.825 ;
     RECT  101.245 5.775 103.145 78.225 ;
     RECT  101.815 165.935 104.905 174.825 ;
     RECT  103.145 5.775 105.045 77.805 ;
     RECT  101.245 81.655 105.095 161.525 ;
     RECT  105.095 81.375 105.235 161.525 ;
     RECT  105.235 143.395 106.045 161.525 ;
     RECT  104.905 164.395 106.045 174.825 ;
     RECT  105.235 81.375 107.185 140.525 ;
     RECT  107.185 80.395 108.135 140.525 ;
     RECT  108.135 79.835 108.705 140.525 ;
     RECT  106.045 143.395 108.705 174.825 ;
     RECT  105.045 5.775 109.655 76.965 ;
     RECT  108.705 79.835 109.655 174.825 ;
     RECT  109.655 5.775 111.81 174.825 ;
     RECT  111.81 4.13 112.27 175.07 ;
     RECT  112.27 5.53 113.91 175.07 ;
     RECT  113.91 5.53 114.37 176.47 ;
     RECT  114.37 29.855 115.305 174.825 ;
     RECT  115.305 30.135 115.495 174.825 ;
     RECT  115.495 36.015 116.445 174.825 ;
     RECT  116.445 151.655 116.825 174.825 ;
     RECT  116.445 36.015 118.155 147.945 ;
     RECT  114.37 5.775 118.585 26.985 ;
     RECT  115.495 30.135 118.585 33.145 ;
     RECT  118.155 36.015 119.105 147.665 ;
     RECT  119.105 36.015 119.865 119.945 ;
     RECT  118.585 5.775 120.245 33.145 ;
     RECT  120.245 14.315 120.485 33.145 ;
     RECT  119.865 36.015 120.485 89.425 ;
     RECT  119.865 92.575 121.005 119.945 ;
     RECT  120.485 14.315 121.195 89.425 ;
     RECT  116.825 151.935 121.435 174.825 ;
     RECT  119.105 122.815 121.625 147.665 ;
     RECT  121.625 122.815 122.005 148.505 ;
     RECT  121.435 151.375 122.005 174.825 ;
     RECT  121.195 20.755 122.335 51.625 ;
     RECT  121.005 93.135 122.955 119.945 ;
     RECT  122.005 122.815 122.955 174.825 ;
     RECT  122.335 36.855 123.925 51.625 ;
     RECT  121.195 14.315 124.285 17.745 ;
     RECT  122.335 20.755 124.285 33.985 ;
     RECT  123.925 36.995 124.425 51.625 ;
     RECT  122.955 93.135 124.475 174.825 ;
     RECT  121.195 54.775 124.855 89.425 ;
     RECT  124.475 92.855 124.855 174.825 ;
     RECT  124.855 54.775 125.185 174.825 ;
     RECT  120.245 5.775 125.235 10.885 ;
     RECT  125.185 54.775 125.755 167.685 ;
     RECT  125.235 5.075 126.135 10.885 ;
     RECT  125.755 54.775 126.325 150.465 ;
     RECT  126.135 5.775 126.375 10.885 ;
     RECT  124.285 14.315 126.375 33.985 ;
     RECT  126.325 54.775 126.705 150.325 ;
     RECT  126.375 5.775 126.755 33.985 ;
     RECT  126.755 5.775 126.79 34.125 ;
     RECT  126.705 54.775 126.895 77.245 ;
     RECT  126.79 5.775 127.895 34.265 ;
     RECT  124.425 37.135 127.895 51.625 ;
     RECT  126.895 54.775 128.415 76.965 ;
     RECT  125.755 153.895 128.655 167.685 ;
     RECT  125.185 171.255 128.655 174.825 ;
     RECT  127.895 5.775 129.035 51.625 ;
     RECT  128.415 54.775 129.035 62.405 ;
     RECT  128.415 65.275 129.795 76.965 ;
     RECT  129.795 65.275 129.985 77.105 ;
     RECT  126.705 80.395 129.985 150.325 ;
     RECT  128.655 153.895 129.985 174.825 ;
     RECT  129.985 65.275 130.315 174.825 ;
     RECT  130.315 142.975 131.265 174.825 ;
     RECT  131.265 143.255 131.645 174.825 ;
     RECT  131.645 143.535 131.835 174.825 ;
     RECT  131.835 165.935 131.885 174.825 ;
     RECT  129.035 5.775 132.215 62.405 ;
     RECT  131.835 143.535 132.595 163.065 ;
     RECT  132.595 143.535 133.355 162.085 ;
     RECT  132.215 57.855 133.595 62.405 ;
     RECT  130.315 65.275 133.595 139.685 ;
     RECT  133.595 57.855 135.495 139.685 ;
     RECT  133.355 143.535 135.495 147.245 ;
     RECT  132.215 5.775 137.585 54.985 ;
     RECT  135.495 57.855 137.585 147.245 ;
     RECT  137.585 5.775 137.81 147.385 ;
     RECT  133.355 150.395 137.81 162.085 ;
     RECT  131.885 165.935 137.81 175.245 ;
     RECT  137.81 4.13 138.27 175.245 ;
     RECT  138.27 5.075 139.435 175.245 ;
     RECT  139.435 5.53 139.91 175.245 ;
     RECT  139.91 5.53 140.37 176.47 ;
     RECT  140.37 115.115 140.575 175.245 ;
     RECT  140.37 5.775 141.335 107.205 ;
     RECT  140.575 151.375 141.335 175.245 ;
     RECT  141.335 34.615 141.715 107.205 ;
     RECT  141.715 34.615 143.045 94.885 ;
     RECT  141.335 155.855 143.615 175.245 ;
     RECT  143.045 57.995 143.805 79.345 ;
     RECT  140.575 115.115 143.805 147.665 ;
     RECT  140.37 110.355 144.235 111.685 ;
     RECT  143.805 115.115 144.235 142.485 ;
     RECT  141.335 5.775 144.27 31.745 ;
     RECT  143.045 34.615 144.27 54.985 ;
     RECT  141.335 151.375 144.615 152.285 ;
     RECT  143.615 155.855 144.615 166.845 ;
     RECT  144.615 151.375 144.995 166.845 ;
     RECT  143.805 146.055 145.185 147.665 ;
     RECT  145.185 146.055 145.38 148.225 ;
     RECT  144.995 151.095 145.38 166.845 ;
     RECT  144.235 110.355 145.515 142.485 ;
     RECT  143.045 82.215 145.705 94.885 ;
     RECT  141.715 98.595 145.895 107.205 ;
     RECT  145.895 100.135 146.085 107.205 ;
     RECT  145.515 110.355 146.275 136.885 ;
     RECT  145.515 140.735 146.465 142.485 ;
     RECT  145.38 146.055 146.465 166.845 ;
     RECT  143.805 71.295 147.225 79.345 ;
     RECT  143.805 57.995 147.465 68.285 ;
     RECT  147.225 71.295 147.465 79.205 ;
     RECT  145.705 94.255 147.465 94.885 ;
     RECT  146.465 140.875 147.605 142.485 ;
     RECT  146.465 146.055 147.795 166.705 ;
     RECT  147.795 146.055 148.175 157.885 ;
     RECT  144.27 5.775 148.365 54.985 ;
     RECT  147.795 161.315 148.555 166.705 ;
     RECT  147.465 94.255 148.605 97.265 ;
     RECT  148.365 5.775 148.935 22.085 ;
     RECT  148.605 94.115 148.935 97.265 ;
     RECT  145.705 82.215 149.125 91.245 ;
     RECT  146.085 105.735 149.175 107.205 ;
     RECT  146.275 110.355 149.175 136.745 ;
     RECT  149.175 105.735 149.365 136.745 ;
     RECT  143.615 169.715 149.505 175.245 ;
     RECT  148.555 161.455 149.555 166.705 ;
     RECT  149.505 169.715 149.555 174.405 ;
     RECT  149.365 105.455 149.885 136.745 ;
     RECT  146.085 100.135 149.935 101.745 ;
     RECT  149.885 105.455 149.935 111.545 ;
     RECT  147.605 140.875 150.075 142.345 ;
     RECT  148.935 94.115 150.455 97.125 ;
     RECT  148.365 25.655 150.695 54.985 ;
     RECT  147.465 57.995 150.695 79.205 ;
     RECT  150.695 25.655 150.835 79.205 ;
     RECT  150.455 94.115 150.835 96.985 ;
     RECT  149.555 161.455 150.835 174.405 ;
     RECT  148.935 6.335 151.025 22.085 ;
     RECT  150.835 94.115 151.025 96.845 ;
     RECT  150.075 141.575 151.215 142.345 ;
     RECT  150.835 25.655 151.265 29.085 ;
     RECT  148.175 146.335 151.265 157.885 ;
     RECT  151.265 146.195 151.405 157.885 ;
     RECT  149.935 100.135 151.595 111.545 ;
     RECT  151.265 25.515 151.645 29.085 ;
     RECT  151.405 151.515 151.645 157.885 ;
     RECT  150.835 161.455 151.645 174.265 ;
     RECT  151.215 141.575 151.975 142.205 ;
     RECT  151.025 8.715 152.025 22.085 ;
     RECT  151.645 25.375 152.025 29.085 ;
     RECT  150.835 31.955 152.215 79.205 ;
     RECT  149.125 82.215 152.215 90.685 ;
     RECT  151.595 100.135 152.215 101.605 ;
     RECT  152.215 99.995 152.355 101.605 ;
     RECT  152.025 8.715 152.735 29.085 ;
     RECT  149.885 115.115 152.975 136.745 ;
     RECT  152.215 31.955 153.115 90.685 ;
     RECT  152.355 99.995 153.39 100.765 ;
     RECT  151.645 151.515 153.685 174.265 ;
     RECT  152.735 25.935 153.735 29.085 ;
     RECT  153.115 31.955 153.735 42.385 ;
     RECT  151.595 105.455 153.735 111.545 ;
     RECT  152.975 115.115 153.735 136.885 ;
     RECT  153.115 45.255 153.875 90.685 ;
     RECT  153.685 161.175 153.875 173.145 ;
     RECT  153.875 45.255 154.065 77.385 ;
     RECT  153.735 105.455 154.065 136.885 ;
     RECT  151.025 94.395 154.115 96.845 ;
     RECT  153.39 99.855 154.115 100.765 ;
     RECT  153.875 161.175 154.255 172.865 ;
     RECT  154.115 94.395 154.305 100.765 ;
     RECT  154.065 105.595 154.445 132.405 ;
     RECT  154.065 135.555 154.495 136.885 ;
     RECT  154.305 94.255 154.635 100.765 ;
     RECT  153.735 25.935 154.825 42.385 ;
     RECT  151.405 146.195 154.825 148.225 ;
     RECT  154.495 135.555 155.015 138.005 ;
     RECT  151.975 141.715 155.255 142.205 ;
     RECT  154.065 45.675 155.395 77.385 ;
     RECT  155.255 141.715 155.53 142.625 ;
     RECT  154.445 109.935 155.965 132.405 ;
     RECT  154.825 25.935 156.015 29.645 ;
     RECT  154.825 32.655 156.155 42.385 ;
     RECT  155.395 47.775 156.155 77.385 ;
     RECT  155.965 109.935 156.155 111.545 ;
     RECT  156.155 40.495 156.205 42.385 ;
     RECT  154.635 94.255 156.205 97.685 ;
     RECT  154.635 100.695 156.205 100.765 ;
     RECT  155.015 135.695 156.395 138.005 ;
     RECT  155.53 141.715 156.395 142.485 ;
     RECT  156.015 25.795 156.585 29.645 ;
     RECT  153.875 81.935 156.775 90.685 ;
     RECT  153.685 151.515 156.775 157.885 ;
     RECT  154.255 161.175 156.775 171.885 ;
     RECT  156.775 81.375 157.155 90.685 ;
     RECT  156.205 94.115 157.155 97.685 ;
     RECT  156.205 100.695 157.345 101.605 ;
     RECT  156.395 135.695 157.485 142.485 ;
     RECT  157.155 81.375 157.535 97.685 ;
     RECT  157.345 100.695 157.535 102.025 ;
     RECT  156.775 151.515 157.675 171.885 ;
     RECT  152.735 8.715 157.865 22.085 ;
     RECT  156.205 40.495 158.105 42.525 ;
     RECT  157.675 160.195 158.245 171.885 ;
     RECT  158.105 40.495 158.26 42.805 ;
     RECT  154.825 146.475 158.295 148.225 ;
     RECT  156.155 47.915 158.435 77.385 ;
     RECT  157.675 151.515 158.435 157.325 ;
     RECT  157.535 81.375 158.485 102.025 ;
     RECT  154.445 105.595 158.485 106.925 ;
     RECT  155.965 115.115 158.485 132.405 ;
     RECT  157.485 135.695 158.485 142.205 ;
     RECT  157.865 10.255 158.625 22.085 ;
     RECT  158.435 54.775 158.675 77.385 ;
     RECT  158.485 81.375 158.675 106.925 ;
     RECT  158.625 10.395 158.815 22.085 ;
     RECT  156.585 25.655 158.865 29.645 ;
     RECT  156.155 32.655 158.865 36.925 ;
     RECT  158.815 11.235 159.055 22.085 ;
     RECT  158.26 40.495 159.055 42.945 ;
     RECT  158.675 54.775 159.195 106.925 ;
     RECT  158.245 160.195 159.195 171.045 ;
     RECT  159.055 11.235 159.245 22.785 ;
     RECT  158.865 25.655 159.245 36.925 ;
     RECT  156.155 110.355 159.245 111.545 ;
     RECT  158.485 115.115 159.245 142.205 ;
     RECT  159.245 11.235 159.385 37.485 ;
     RECT  158.295 146.055 159.385 148.225 ;
     RECT  159.055 40.495 159.435 43.085 ;
     RECT  158.435 47.915 159.435 51.625 ;
     RECT  159.195 104.475 159.435 106.925 ;
     RECT  159.385 11.515 159.575 37.485 ;
     RECT  159.195 160.195 159.765 170.065 ;
     RECT  159.575 37.415 159.815 37.485 ;
     RECT  159.435 40.495 159.815 51.625 ;
     RECT  159.575 14.315 159.955 34.545 ;
     RECT  159.815 37.415 159.955 51.625 ;
     RECT  159.955 14.315 160.145 15.225 ;
     RECT  159.195 54.775 160.335 101.605 ;
     RECT  159.245 110.355 160.335 142.205 ;
     RECT  159.765 165.935 160.335 170.065 ;
     RECT  159.435 104.475 160.385 107.205 ;
     RECT  160.335 110.355 160.385 112.945 ;
     RECT  160.145 14.455 160.525 15.225 ;
     RECT  160.335 115.955 160.525 142.205 ;
     RECT  160.525 115.955 160.715 142.065 ;
     RECT  159.955 18.795 160.905 34.545 ;
     RECT  158.435 151.655 161.715 157.325 ;
     RECT  159.765 160.195 161.715 162.085 ;
     RECT  159.385 146.335 162.285 148.225 ;
     RECT  160.335 81.375 162.475 101.605 ;
     RECT  160.385 104.475 162.475 112.945 ;
     RECT  160.335 54.775 163.235 78.225 ;
     RECT  162.475 81.375 163.235 112.945 ;
     RECT  160.905 20.335 163.81 34.545 ;
     RECT  159.955 37.415 163.81 51.345 ;
     RECT  163.235 54.775 163.81 112.945 ;
     RECT  160.715 115.955 163.81 132.825 ;
     RECT  160.715 135.695 163.81 142.065 ;
     RECT  162.285 146.055 163.81 148.225 ;
     RECT  161.715 151.655 163.81 162.085 ;
     RECT  160.335 165.935 163.81 167.545 ;
     RECT  163.81 4.13 164.27 175.07 ;
     RECT  164.27 5.53 165.91 175.07 ;
     RECT  165.91 5.53 166.37 176.47 ;
     RECT  166.37 26.215 166.415 26.285 ;
     RECT  166.37 29.855 166.605 31.885 ;
     RECT  166.605 30.135 166.795 31.885 ;
     RECT  166.37 140.175 166.795 142.345 ;
     RECT  166.37 38.395 167.175 87.885 ;
     RECT  166.37 114.975 167.175 135.345 ;
     RECT  166.795 140.175 167.175 140.945 ;
     RECT  166.37 145.775 167.365 152.005 ;
     RECT  167.175 39.795 167.555 87.885 ;
     RECT  167.365 145.775 167.935 147.385 ;
     RECT  167.365 150.395 168.125 152.005 ;
     RECT  166.795 31.815 168.315 31.885 ;
     RECT  167.555 39.795 168.505 87.745 ;
     RECT  167.175 114.975 168.505 133.665 ;
     RECT  168.505 39.935 169.075 87.745 ;
     RECT  166.37 91.455 169.265 111.125 ;
     RECT  169.265 91.455 169.455 104.825 ;
     RECT  169.075 39.935 169.645 42.245 ;
     RECT  169.075 46.795 169.645 87.745 ;
     RECT  169.645 47.075 169.835 87.745 ;
     RECT  167.175 140.175 169.835 140.805 ;
     RECT  169.835 49.595 170.405 87.745 ;
     RECT  168.125 150.395 170.405 150.465 ;
     RECT  167.935 145.775 170.595 145.845 ;
     RECT  169.835 140.735 170.785 140.805 ;
     RECT  168.505 114.975 171.355 132.545 ;
     RECT  169.265 108.395 171.405 111.125 ;
     RECT  169.645 39.935 171.545 40.005 ;
     RECT  170.405 49.595 171.545 87.605 ;
     RECT  171.405 108.395 171.785 111.265 ;
     RECT  171.545 54.355 171.925 87.605 ;
     RECT  171.785 108.395 171.975 111.545 ;
     RECT  169.455 91.455 172.165 92.085 ;
     RECT  171.545 49.595 172.875 51.205 ;
     RECT  171.975 108.395 173.065 111.685 ;
     RECT  171.355 115.955 173.065 132.545 ;
     RECT  173.065 115.955 173.255 131.005 ;
     RECT  172.165 90.755 173.305 92.085 ;
     RECT  169.455 95.375 173.305 104.685 ;
     RECT  171.925 54.355 173.445 65.625 ;
     RECT  173.305 90.755 173.445 104.685 ;
     RECT  173.065 109.235 173.445 111.685 ;
     RECT  173.445 54.355 173.635 65.345 ;
     RECT  173.635 54.915 174.015 65.205 ;
     RECT  173.445 109.235 174.015 109.305 ;
     RECT  174.015 54.915 174.395 64.925 ;
     RECT  173.255 115.955 174.445 127.225 ;
     RECT  174.395 62.335 174.585 64.925 ;
     RECT  174.445 115.535 174.585 127.225 ;
     RECT  174.585 125.335 174.775 127.225 ;
     RECT  171.925 69.335 175.155 87.605 ;
     RECT  174.395 54.915 175.345 59.045 ;
     RECT  175.345 58.975 175.535 59.045 ;
     RECT  174.585 62.335 175.725 62.825 ;
     RECT  175.155 69.475 175.725 87.605 ;
     RECT  175.725 71.715 175.775 87.605 ;
     RECT  173.445 90.755 175.775 104.545 ;
     RECT  175.725 62.475 175.915 62.825 ;
     RECT  175.915 62.475 176.105 62.545 ;
     RECT  172.875 51.135 176.295 51.205 ;
     RECT  175.775 71.715 176.345 104.545 ;
     RECT  175.345 54.915 176.485 54.985 ;
     RECT  174.585 115.535 176.485 122.465 ;
     RECT  176.345 112.175 178.195 112.245 ;
     RECT  176.345 71.715 178.245 106.505 ;
     RECT  176.485 116.935 178.575 122.465 ;
     RECT  173.255 130.515 178.765 131.005 ;
     RECT  178.575 119.595 178.955 122.465 ;
     RECT  178.765 130.935 179.145 131.005 ;
     RECT  178.955 122.395 179.335 122.465 ;
     RECT  174.775 125.335 179.525 125.405 ;
     RECT  178.245 71.715 179.63 107.625 ;
    LAYER metal4 ;
     RECT  7.79 4.13 8.29 5.53 ;
     RECT  33.79 4.13 34.29 5.53 ;
     RECT  59.79 4.13 60.29 5.53 ;
     RECT  85.79 4.13 86.29 5.53 ;
     RECT  111.79 4.13 112.29 5.53 ;
     RECT  137.79 4.13 138.29 5.53 ;
     RECT  163.79 4.13 164.29 5.53 ;
     RECT  59.79 5.53 62.39 6.44 ;
     RECT  59.79 6.44 65.405 6.72 ;
     RECT  59.79 6.72 65.965 6.86 ;
     RECT  59.79 6.86 65.405 10.36 ;
     RECT  59.79 10.36 62.39 10.5 ;
     RECT  33.79 5.53 36.39 12.6 ;
     RECT  59.105 10.5 62.39 15.96 ;
     RECT  29.425 12.6 36.39 16.38 ;
     RECT  17.665 7.56 17.805 18.62 ;
     RECT  70.865 21.14 71.005 25.9 ;
     RECT  59.79 15.96 62.39 26.6 ;
     RECT  70.865 25.9 72.405 28 ;
     RECT  7.79 5.53 10.39 28.28 ;
     RECT  33.79 16.38 36.39 36.68 ;
     RECT  124.065 24.92 124.205 36.82 ;
     RECT  123.785 36.82 124.205 37.94 ;
     RECT  124.065 37.94 124.205 38.08 ;
     RECT  33.345 36.68 36.39 38.64 ;
     RECT  59.79 26.6 62.885 38.92 ;
     RECT  137.79 5.53 140.39 39.34 ;
     RECT  4.505 28.28 10.39 39.9 ;
     RECT  70.865 28 71.005 39.9 ;
     RECT  137.225 39.34 140.39 40.88 ;
     RECT  131.905 40.88 140.39 43.12 ;
     RECT  3.665 39.9 11.645 45.5 ;
     RECT  3.665 45.5 13.885 45.64 ;
     RECT  3.385 45.64 13.885 45.67 ;
     RECT  3.385 45.67 12.765 49.98 ;
     RECT  33.79 38.64 36.39 51.24 ;
     RECT  131.905 43.12 132.045 51.38 ;
     RECT  30.545 51.24 36.39 52.36 ;
     RECT  52.385 51.1 52.525 53.2 ;
     RECT  3.665 49.98 12.765 53.34 ;
     RECT  51.825 53.2 52.525 53.48 ;
     RECT  59.79 38.92 62.39 53.48 ;
     RECT  30.545 52.36 40.205 54.32 ;
     RECT  30.545 54.32 36.39 55.3 ;
     RECT  3.665 53.34 18.085 57.12 ;
     RECT  3.665 57.12 15.845 57.26 ;
     RECT  3.665 57.26 14.725 57.68 ;
     RECT  69.185 56.7 69.325 58.8 ;
     RECT  51.825 53.48 62.39 59.78 ;
     RECT  103.905 52.36 104.045 59.78 ;
     RECT  103.065 59.78 104.045 59.92 ;
     RECT  150.385 38.36 150.525 60.34 ;
     RECT  163.79 5.53 166.39 60.76 ;
     RECT  54.625 59.78 62.39 61.88 ;
     RECT  3.665 57.68 12.765 66.22 ;
     RECT  3.665 66.22 18.085 66.5 ;
     RECT  33.79 55.3 36.39 68.04 ;
     RECT  3.665 66.5 10.805 68.32 ;
     RECT  33.345 68.04 36.39 68.46 ;
     RECT  28.585 68.46 36.39 70.42 ;
     RECT  3.385 68.32 10.805 71.96 ;
     RECT  3.105 71.96 10.805 72.1 ;
     RECT  17.665 66.5 18.085 76.72 ;
     RECT  17.945 76.72 18.085 77 ;
     RECT  73.945 76.58 74.085 77.98 ;
     RECT  54.625 61.88 64.005 79.66 ;
     RECT  85.79 5.53 88.39 79.8 ;
     RECT  59.79 79.66 64.005 83.44 ;
     RECT  24.385 84.28 24.525 85.68 ;
     RECT  137.79 43.12 140.39 89.18 ;
     RECT  17.665 87.5 17.805 91.56 ;
     RECT  59.79 83.44 66.805 92.12 ;
     RECT  127.705 81.9 127.845 94.08 ;
     RECT  44.825 79.8 44.965 94.92 ;
     RECT  103.065 59.92 103.205 95.34 ;
     RECT  81.785 79.8 88.39 95.62 ;
     RECT  59.79 92.12 65.125 96.88 ;
     RECT  17.385 91.56 17.805 97.3 ;
     RECT  17.385 97.3 17.525 97.72 ;
     RECT  77.025 95.9 77.165 98.28 ;
     RECT  33.79 70.42 36.39 99.68 ;
     RECT  33.79 99.68 37.405 99.82 ;
     RECT  111.79 5.53 114.39 99.82 ;
     RECT  3.105 72.1 10.39 100.8 ;
     RECT  32.225 99.82 37.405 101.78 ;
     RECT  32.225 101.78 37.685 103.04 ;
     RECT  32.225 103.04 37.405 103.88 ;
     RECT  59.79 96.88 64.005 105.38 ;
     RECT  2.825 100.8 10.39 106.12 ;
     RECT  131.625 102.76 131.765 106.26 ;
     RECT  111.185 99.82 114.39 107.52 ;
     RECT  107.265 107.52 114.39 108.78 ;
     RECT  105.585 108.78 114.39 109.76 ;
     RECT  161.305 60.76 166.39 110.88 ;
     RECT  2.545 106.12 10.39 112.84 ;
     RECT  128.825 106.26 131.765 115.5 ;
     RECT  161.305 110.88 167.045 116.76 ;
     RECT  2.825 112.84 10.39 118.44 ;
     RECT  124.065 115.5 131.765 118.58 ;
     RECT  3.105 118.44 10.39 118.86 ;
     RECT  124.065 118.58 128.965 119 ;
     RECT  123.505 119 128.965 119.28 ;
     RECT  123.505 119.28 124.205 119.42 ;
     RECT  33.79 103.88 37.405 119.7 ;
     RECT  111.185 109.76 114.39 119.7 ;
     RECT  123.505 119.42 123.645 119.7 ;
     RECT  85.79 95.62 88.39 121.1 ;
     RECT  137.79 89.18 142.125 122.5 ;
     RECT  161.305 116.76 166.39 124.18 ;
     RECT  85.79 121.1 93.125 125.86 ;
     RECT  82.065 125.86 93.125 127.12 ;
     RECT  23.265 127.12 23.405 127.68 ;
     RECT  3.105 118.86 13.045 127.82 ;
     RECT  19.625 127.68 23.405 127.82 ;
     RECT  85.79 127.12 93.125 128.38 ;
     RECT  111.79 119.7 114.39 130.34 ;
     RECT  122.945 128.1 123.085 131.18 ;
     RECT  3.105 127.82 23.405 136.92 ;
     RECT  137.79 122.5 142.405 138.04 ;
     RECT  111.185 130.34 114.39 138.88 ;
     RECT  7.79 136.92 23.405 139.44 ;
     RECT  7.79 139.44 19.765 139.58 ;
     RECT  85.79 128.38 88.39 140.14 ;
     RECT  59.79 105.38 64.285 140.98 ;
     RECT  7.79 139.58 15.285 142.1 ;
     RECT  59.79 140.98 62.39 142.38 ;
     RECT  7.79 142.1 13.605 143.22 ;
     RECT  85.79 140.14 92.285 144.9 ;
     RECT  137.79 138.04 142.125 144.9 ;
     RECT  56.585 142.38 62.39 145.46 ;
     RECT  4.785 143.22 13.605 147.7 ;
     RECT  25.225 145.74 25.365 148.68 ;
     RECT  146.745 149.8 146.885 151.06 ;
     RECT  7.79 147.7 13.605 153.72 ;
     RECT  23.265 148.68 25.365 153.72 ;
     RECT  7.79 153.72 25.365 154.84 ;
     RECT  18.785 154.84 25.365 156.1 ;
     RECT  7.79 154.84 12.765 159.6 ;
     RECT  23.265 156.1 25.365 159.6 ;
     RECT  3.385 159.6 12.765 160.86 ;
     RECT  59.79 145.46 62.39 160.86 ;
     RECT  59.79 160.86 62.885 163.24 ;
     RECT  7.79 160.86 12.765 163.66 ;
     RECT  7.79 163.66 14.165 165.9 ;
     RECT  7.79 165.9 12.485 166.04 ;
     RECT  7.79 166.04 10.39 175.07 ;
     RECT  33.79 119.7 36.39 175.07 ;
     RECT  59.79 163.24 62.39 175.07 ;
     RECT  85.79 144.9 88.39 175.07 ;
     RECT  111.79 138.88 114.39 175.07 ;
     RECT  137.79 144.9 140.39 175.07 ;
     RECT  163.79 124.18 166.39 175.07 ;
     RECT  9.89 175.07 10.39 176.47 ;
     RECT  35.89 175.07 36.39 176.47 ;
     RECT  61.89 175.07 62.39 176.47 ;
     RECT  87.89 175.07 88.39 176.47 ;
     RECT  113.89 175.07 114.39 176.47 ;
     RECT  139.89 175.07 140.39 176.47 ;
     RECT  165.89 175.07 166.39 176.47 ;
    LAYER metal5 ;
     RECT  3.385 45.64 4.645 45.78 ;
     RECT  139.185 39.76 139.325 40.46 ;
     RECT  139.325 39.76 139.605 39.9 ;
     RECT  3.04 11.45 176.51 16.05 ;
     RECT  3.04 71.45 176.51 76.05 ;
     RECT  3.04 131.45 176.51 136.05 ;
    LAYER metal6 ;
     RECT  13.29 4.16 17.89 176.44 ;
     RECT  73.29 4.16 77.89 176.44 ;
     RECT  133.29 4.16 137.89 176.44 ;
  END
END CCM
END LIBRARY
